VERSION 5.7 ;
  NOWIREEXTENSIONATPIN ON ;
  DIVIDERCHAR "/" ;
  BUSBITCHARS "[]" ;
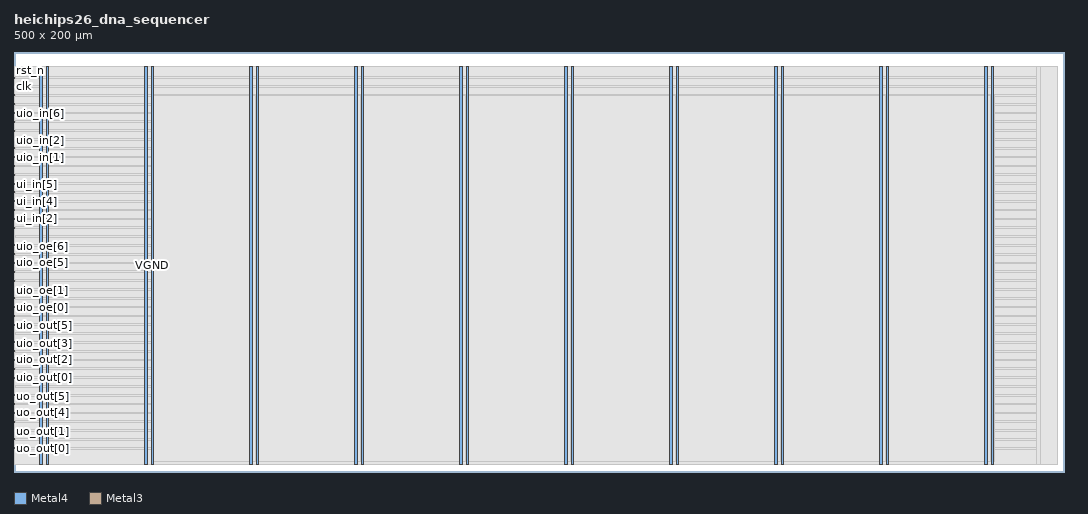
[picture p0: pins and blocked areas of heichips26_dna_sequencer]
MACRO heichips26_dna_sequencer
  CLASS BLOCK ;
  FOREIGN heichips26_dna_sequencer ;
  ORIGIN 0.000 0.000 ;
  SIZE 500.000 BY 200.000 ;
  PIN VGND
    DIRECTION INOUT ;
    USE GROUND ;
    PORT
      LAYER Metal4 ;
        RECT 15.380 3.560 16.380 193.000 ;
    END
    PORT
      LAYER Metal4 ;
        RECT 65.380 3.560 66.380 193.000 ;
    END
    PORT
      LAYER Metal4 ;
        RECT 115.380 3.560 116.380 193.000 ;
    END
    PORT
      LAYER Metal4 ;
        RECT 165.380 3.560 166.380 193.000 ;
    END
    PORT
      LAYER Metal4 ;
        RECT 215.380 3.560 216.380 193.000 ;
    END
    PORT
      LAYER Metal4 ;
        RECT 265.380 3.560 266.380 193.000 ;
    END
    PORT
      LAYER Metal4 ;
        RECT 315.380 3.560 316.380 193.000 ;
    END
    PORT
      LAYER Metal4 ;
        RECT 365.380 3.560 366.380 193.000 ;
    END
    PORT
      LAYER Metal4 ;
        RECT 415.380 3.560 416.380 193.000 ;
    END
    PORT
      LAYER Metal4 ;
        RECT 465.380 3.560 466.380 193.000 ;
    END
  END VGND
  PIN VPWR
    DIRECTION INOUT ;
    USE POWER ;
    PORT
      LAYER Metal4 ;
        RECT 12.380 3.560 13.380 193.000 ;
    END
    PORT
      LAYER Metal4 ;
        RECT 62.380 3.560 63.380 193.000 ;
    END
    PORT
      LAYER Metal4 ;
        RECT 112.380 3.560 113.380 193.000 ;
    END
    PORT
      LAYER Metal4 ;
        RECT 162.380 3.560 163.380 193.000 ;
    END
    PORT
      LAYER Metal4 ;
        RECT 212.380 3.560 213.380 193.000 ;
    END
    PORT
      LAYER Metal4 ;
        RECT 262.380 3.560 263.380 193.000 ;
    END
    PORT
      LAYER Metal4 ;
        RECT 312.380 3.560 313.380 193.000 ;
    END
    PORT
      LAYER Metal4 ;
        RECT 362.380 3.560 363.380 193.000 ;
    END
    PORT
      LAYER Metal4 ;
        RECT 412.380 3.560 413.380 193.000 ;
    END
    PORT
      LAYER Metal4 ;
        RECT 462.380 3.560 463.380 193.000 ;
    END
  END VPWR
  PIN clk
    DIRECTION INPUT ;
    USE SIGNAL ;
    ANTENNAGATEAREA 0.725400 ;
    PORT
      LAYER Metal3 ;
        RECT 0.000 183.340 0.400 183.740 ;
    END
  END clk
  PIN ena
    DIRECTION INPUT ;
    USE SIGNAL ;
    PORT
      LAYER Metal3 ;
        RECT 0.000 179.140 0.400 179.540 ;
    END
  END ena
  PIN rst_n
    DIRECTION INPUT ;
    USE SIGNAL ;
    ANTENNAGATEAREA 0.180700 ;
    PORT
      LAYER Metal3 ;
        RECT 0.000 187.540 0.400 187.940 ;
    END
  END rst_n
  PIN ui_in[0]
    DIRECTION INPUT ;
    USE SIGNAL ;
    ANTENNAGATEAREA 0.180700 ;
    PORT
      LAYER Metal3 ;
        RECT 0.000 111.940 0.400 112.340 ;
    END
  END ui_in[0]
  PIN ui_in[1]
    DIRECTION INPUT ;
    USE SIGNAL ;
    ANTENNAGATEAREA 0.180700 ;
    PORT
      LAYER Metal3 ;
        RECT 0.000 116.140 0.400 116.540 ;
    END
  END ui_in[1]
  PIN ui_in[2]
    DIRECTION INPUT ;
    USE SIGNAL ;
    ANTENNAGATEAREA 0.180700 ;
    PORT
      LAYER Metal3 ;
        RECT 0.000 120.340 0.400 120.740 ;
    END
  END ui_in[2]
  PIN ui_in[3]
    DIRECTION INPUT ;
    USE SIGNAL ;
    ANTENNAGATEAREA 0.180700 ;
    PORT
      LAYER Metal3 ;
        RECT 0.000 124.540 0.400 124.940 ;
    END
  END ui_in[3]
  PIN ui_in[4]
    DIRECTION INPUT ;
    USE SIGNAL ;
    PORT
      LAYER Metal3 ;
        RECT 0.000 128.740 0.400 129.140 ;
    END
  END ui_in[4]
  PIN ui_in[5]
    DIRECTION INPUT ;
    USE SIGNAL ;
    PORT
      LAYER Metal3 ;
        RECT 0.000 132.940 0.400 133.340 ;
    END
  END ui_in[5]
  PIN ui_in[6]
    DIRECTION INPUT ;
    USE SIGNAL ;
    PORT
      LAYER Metal3 ;
        RECT 0.000 137.140 0.400 137.540 ;
    END
  END ui_in[6]
  PIN ui_in[7]
    DIRECTION INPUT ;
    USE SIGNAL ;
    PORT
      LAYER Metal3 ;
        RECT 0.000 141.340 0.400 141.740 ;
    END
  END ui_in[7]
  PIN uio_in[0]
    DIRECTION INPUT ;
    USE SIGNAL ;
    ANTENNAGATEAREA 0.180700 ;
    PORT
      LAYER Metal3 ;
        RECT 0.000 145.540 0.400 145.940 ;
    END
  END uio_in[0]
  PIN uio_in[1]
    DIRECTION INPUT ;
    USE SIGNAL ;
    ANTENNAGATEAREA 0.180700 ;
    PORT
      LAYER Metal3 ;
        RECT 0.000 149.740 0.400 150.140 ;
    END
  END uio_in[1]
  PIN uio_in[2]
    DIRECTION INPUT ;
    USE SIGNAL ;
    ANTENNAGATEAREA 0.180700 ;
    PORT
      LAYER Metal3 ;
        RECT 0.000 153.940 0.400 154.340 ;
    END
  END uio_in[2]
  PIN uio_in[3]
    DIRECTION INPUT ;
    USE SIGNAL ;
    ANTENNAGATEAREA 0.180700 ;
    PORT
      LAYER Metal3 ;
        RECT 0.000 158.140 0.400 158.540 ;
    END
  END uio_in[3]
  PIN uio_in[4]
    DIRECTION INPUT ;
    USE SIGNAL ;
    ANTENNAGATEAREA 0.180700 ;
    PORT
      LAYER Metal3 ;
        RECT 0.000 162.340 0.400 162.740 ;
    END
  END uio_in[4]
  PIN uio_in[5]
    DIRECTION INPUT ;
    USE SIGNAL ;
    ANTENNAGATEAREA 0.180700 ;
    PORT
      LAYER Metal3 ;
        RECT 0.000 166.540 0.400 166.940 ;
    END
  END uio_in[5]
  PIN uio_in[6]
    DIRECTION INPUT ;
    USE SIGNAL ;
    ANTENNAGATEAREA 0.180700 ;
    PORT
      LAYER Metal3 ;
        RECT 0.000 170.740 0.400 171.140 ;
    END
  END uio_in[6]
  PIN uio_in[7]
    DIRECTION INPUT ;
    USE SIGNAL ;
    ANTENNAGATEAREA 0.180700 ;
    PORT
      LAYER Metal3 ;
        RECT 0.000 174.940 0.400 175.340 ;
    END
  END uio_in[7]
  PIN uio_oe[0]
    DIRECTION OUTPUT ;
    USE SIGNAL ;
    ANTENNADIFFAREA 0.299200 ;
    PORT
      LAYER Metal3 ;
        RECT 0.000 78.340 0.400 78.740 ;
    END
  END uio_oe[0]
  PIN uio_oe[1]
    DIRECTION OUTPUT ;
    USE SIGNAL ;
    ANTENNADIFFAREA 0.299200 ;
    PORT
      LAYER Metal3 ;
        RECT 0.000 82.540 0.400 82.940 ;
    END
  END uio_oe[1]
  PIN uio_oe[2]
    DIRECTION OUTPUT ;
    USE SIGNAL ;
    ANTENNADIFFAREA 0.299200 ;
    PORT
      LAYER Metal3 ;
        RECT 0.000 86.740 0.400 87.140 ;
    END
  END uio_oe[2]
  PIN uio_oe[3]
    DIRECTION OUTPUT ;
    USE SIGNAL ;
    ANTENNADIFFAREA 0.299200 ;
    PORT
      LAYER Metal3 ;
        RECT 0.000 90.940 0.400 91.340 ;
    END
  END uio_oe[3]
  PIN uio_oe[4]
    DIRECTION OUTPUT ;
    USE SIGNAL ;
    ANTENNADIFFAREA 0.299200 ;
    PORT
      LAYER Metal3 ;
        RECT 0.000 95.140 0.400 95.540 ;
    END
  END uio_oe[4]
  PIN uio_oe[5]
    DIRECTION OUTPUT ;
    USE SIGNAL ;
    ANTENNADIFFAREA 0.299200 ;
    PORT
      LAYER Metal3 ;
        RECT 0.000 99.340 0.400 99.740 ;
    END
  END uio_oe[5]
  PIN uio_oe[6]
    DIRECTION OUTPUT ;
    USE SIGNAL ;
    ANTENNADIFFAREA 0.299200 ;
    PORT
      LAYER Metal3 ;
        RECT 0.000 103.540 0.400 103.940 ;
    END
  END uio_oe[6]
  PIN uio_oe[7]
    DIRECTION OUTPUT ;
    USE SIGNAL ;
    ANTENNADIFFAREA 0.299200 ;
    PORT
      LAYER Metal3 ;
        RECT 0.000 107.740 0.400 108.140 ;
    END
  END uio_oe[7]
  PIN uio_out[0]
    DIRECTION OUTPUT ;
    USE SIGNAL ;
    ANTENNADIFFAREA 0.299200 ;
    PORT
      LAYER Metal3 ;
        RECT 0.000 44.740 0.400 45.140 ;
    END
  END uio_out[0]
  PIN uio_out[1]
    DIRECTION OUTPUT ;
    USE SIGNAL ;
    ANTENNADIFFAREA 0.299200 ;
    PORT
      LAYER Metal3 ;
        RECT 0.000 48.940 0.400 49.340 ;
    END
  END uio_out[1]
  PIN uio_out[2]
    DIRECTION OUTPUT ;
    USE SIGNAL ;
    ANTENNADIFFAREA 0.299200 ;
    PORT
      LAYER Metal3 ;
        RECT 0.000 53.140 0.400 53.540 ;
    END
  END uio_out[2]
  PIN uio_out[3]
    DIRECTION OUTPUT ;
    USE SIGNAL ;
    ANTENNADIFFAREA 0.299200 ;
    PORT
      LAYER Metal3 ;
        RECT 0.000 57.340 0.400 57.740 ;
    END
  END uio_out[3]
  PIN uio_out[4]
    DIRECTION OUTPUT ;
    USE SIGNAL ;
    ANTENNADIFFAREA 0.299200 ;
    PORT
      LAYER Metal3 ;
        RECT 0.000 61.540 0.400 61.940 ;
    END
  END uio_out[4]
  PIN uio_out[5]
    DIRECTION OUTPUT ;
    USE SIGNAL ;
    ANTENNADIFFAREA 0.299200 ;
    PORT
      LAYER Metal3 ;
        RECT 0.000 65.740 0.400 66.140 ;
    END
  END uio_out[5]
  PIN uio_out[6]
    DIRECTION OUTPUT ;
    USE SIGNAL ;
    ANTENNADIFFAREA 0.299200 ;
    PORT
      LAYER Metal3 ;
        RECT 0.000 69.940 0.400 70.340 ;
    END
  END uio_out[6]
  PIN uio_out[7]
    DIRECTION OUTPUT ;
    USE SIGNAL ;
    ANTENNADIFFAREA 0.299200 ;
    PORT
      LAYER Metal3 ;
        RECT 0.000 74.140 0.400 74.540 ;
    END
  END uio_out[7]
  PIN uo_out[0]
    DIRECTION OUTPUT ;
    USE SIGNAL ;
    ANTENNADIFFAREA 0.708600 ;
    PORT
      LAYER Metal3 ;
        RECT 0.000 11.140 0.400 11.540 ;
    END
  END uo_out[0]
  PIN uo_out[1]
    DIRECTION OUTPUT ;
    USE SIGNAL ;
    ANTENNADIFFAREA 0.708600 ;
    PORT
      LAYER Metal3 ;
        RECT 0.000 15.340 0.400 15.740 ;
    END
  END uo_out[1]
  PIN uo_out[2]
    DIRECTION OUTPUT ;
    USE SIGNAL ;
    ANTENNADIFFAREA 0.708600 ;
    PORT
      LAYER Metal3 ;
        RECT 0.000 19.540 0.400 19.940 ;
    END
  END uo_out[2]
  PIN uo_out[3]
    DIRECTION OUTPUT ;
    USE SIGNAL ;
    ANTENNADIFFAREA 0.708600 ;
    PORT
      LAYER Metal3 ;
        RECT 0.000 23.740 0.400 24.140 ;
    END
  END uo_out[3]
  PIN uo_out[4]
    DIRECTION OUTPUT ;
    USE SIGNAL ;
    ANTENNADIFFAREA 0.708600 ;
    PORT
      LAYER Metal3 ;
        RECT 0.000 27.940 0.400 28.340 ;
    END
  END uo_out[4]
  PIN uo_out[5]
    DIRECTION OUTPUT ;
    USE SIGNAL ;
    ANTENNADIFFAREA 0.708600 ;
    PORT
      LAYER Metal3 ;
        RECT 0.000 32.140 0.400 32.540 ;
    END
  END uo_out[5]
  PIN uo_out[6]
    DIRECTION OUTPUT ;
    USE SIGNAL ;
    ANTENNADIFFAREA 0.299200 ;
    PORT
      LAYER Metal3 ;
        RECT 0.000 36.340 0.400 36.740 ;
    END
  END uo_out[6]
  PIN uo_out[7]
    DIRECTION OUTPUT ;
    USE SIGNAL ;
    ANTENNADIFFAREA 0.299200 ;
    PORT
      LAYER Metal3 ;
        RECT 0.000 40.540 0.400 40.940 ;
    END
  END uo_out[7]
  OBS
      LAYER GatPoly ;
        RECT 2.880 3.630 496.800 192.930 ;
      LAYER Metal1 ;
        RECT 2.880 3.560 496.800 193.000 ;
      LAYER Metal2 ;
        RECT 0.375 3.635 488.740 192.925 ;
      LAYER Metal3 ;
        RECT 0.335 188.150 486.865 192.880 ;
        RECT 0.610 187.330 486.865 188.150 ;
        RECT 0.335 183.950 486.865 187.330 ;
        RECT 0.610 183.130 486.865 183.950 ;
        RECT 0.335 179.750 486.865 183.130 ;
        RECT 0.610 178.930 486.865 179.750 ;
        RECT 0.335 175.550 486.865 178.930 ;
        RECT 0.610 174.730 486.865 175.550 ;
        RECT 0.335 171.350 486.865 174.730 ;
        RECT 0.610 170.530 486.865 171.350 ;
        RECT 0.335 167.150 486.865 170.530 ;
        RECT 0.610 166.330 486.865 167.150 ;
        RECT 0.335 162.950 486.865 166.330 ;
        RECT 0.610 162.130 486.865 162.950 ;
        RECT 0.335 158.750 486.865 162.130 ;
        RECT 0.610 157.930 486.865 158.750 ;
        RECT 0.335 154.550 486.865 157.930 ;
        RECT 0.610 153.730 486.865 154.550 ;
        RECT 0.335 150.350 486.865 153.730 ;
        RECT 0.610 149.530 486.865 150.350 ;
        RECT 0.335 146.150 486.865 149.530 ;
        RECT 0.610 145.330 486.865 146.150 ;
        RECT 0.335 141.950 486.865 145.330 ;
        RECT 0.610 141.130 486.865 141.950 ;
        RECT 0.335 137.750 486.865 141.130 ;
        RECT 0.610 136.930 486.865 137.750 ;
        RECT 0.335 133.550 486.865 136.930 ;
        RECT 0.610 132.730 486.865 133.550 ;
        RECT 0.335 129.350 486.865 132.730 ;
        RECT 0.610 128.530 486.865 129.350 ;
        RECT 0.335 125.150 486.865 128.530 ;
        RECT 0.610 124.330 486.865 125.150 ;
        RECT 0.335 120.950 486.865 124.330 ;
        RECT 0.610 120.130 486.865 120.950 ;
        RECT 0.335 116.750 486.865 120.130 ;
        RECT 0.610 115.930 486.865 116.750 ;
        RECT 0.335 112.550 486.865 115.930 ;
        RECT 0.610 111.730 486.865 112.550 ;
        RECT 0.335 108.350 486.865 111.730 ;
        RECT 0.610 107.530 486.865 108.350 ;
        RECT 0.335 104.150 486.865 107.530 ;
        RECT 0.610 103.330 486.865 104.150 ;
        RECT 0.335 99.950 486.865 103.330 ;
        RECT 0.610 99.130 486.865 99.950 ;
        RECT 0.335 95.750 486.865 99.130 ;
        RECT 0.610 94.930 486.865 95.750 ;
        RECT 0.335 91.550 486.865 94.930 ;
        RECT 0.610 90.730 486.865 91.550 ;
        RECT 0.335 87.350 486.865 90.730 ;
        RECT 0.610 86.530 486.865 87.350 ;
        RECT 0.335 83.150 486.865 86.530 ;
        RECT 0.610 82.330 486.865 83.150 ;
        RECT 0.335 78.950 486.865 82.330 ;
        RECT 0.610 78.130 486.865 78.950 ;
        RECT 0.335 74.750 486.865 78.130 ;
        RECT 0.610 73.930 486.865 74.750 ;
        RECT 0.335 70.550 486.865 73.930 ;
        RECT 0.610 69.730 486.865 70.550 ;
        RECT 0.335 66.350 486.865 69.730 ;
        RECT 0.610 65.530 486.865 66.350 ;
        RECT 0.335 62.150 486.865 65.530 ;
        RECT 0.610 61.330 486.865 62.150 ;
        RECT 0.335 57.950 486.865 61.330 ;
        RECT 0.610 57.130 486.865 57.950 ;
        RECT 0.335 53.750 486.865 57.130 ;
        RECT 0.610 52.930 486.865 53.750 ;
        RECT 0.335 49.550 486.865 52.930 ;
        RECT 0.610 48.730 486.865 49.550 ;
        RECT 0.335 45.350 486.865 48.730 ;
        RECT 0.610 44.530 486.865 45.350 ;
        RECT 0.335 41.150 486.865 44.530 ;
        RECT 0.610 40.330 486.865 41.150 ;
        RECT 0.335 36.950 486.865 40.330 ;
        RECT 0.610 36.130 486.865 36.950 ;
        RECT 0.335 32.750 486.865 36.130 ;
        RECT 0.610 31.930 486.865 32.750 ;
        RECT 0.335 28.550 486.865 31.930 ;
        RECT 0.610 27.730 486.865 28.550 ;
        RECT 0.335 24.350 486.865 27.730 ;
        RECT 0.610 23.530 486.865 24.350 ;
        RECT 0.335 20.150 486.865 23.530 ;
        RECT 0.610 19.330 486.865 20.150 ;
        RECT 0.335 15.950 486.865 19.330 ;
        RECT 0.610 15.130 486.865 15.950 ;
        RECT 0.335 11.750 486.865 15.130 ;
        RECT 0.610 10.930 486.865 11.750 ;
        RECT 0.335 3.680 486.865 10.930 ;
      LAYER Metal4 ;
        RECT 66.620 4.895 112.170 179.065 ;
        RECT 113.590 4.895 115.170 179.065 ;
        RECT 116.590 4.895 162.170 179.065 ;
        RECT 163.590 4.895 165.170 179.065 ;
        RECT 166.590 4.895 212.170 179.065 ;
        RECT 213.590 4.895 215.170 179.065 ;
        RECT 216.590 4.895 262.170 179.065 ;
        RECT 263.590 4.895 265.170 179.065 ;
        RECT 266.590 4.895 312.170 179.065 ;
        RECT 313.590 4.895 315.170 179.065 ;
        RECT 316.590 4.895 362.170 179.065 ;
        RECT 363.590 4.895 365.170 179.065 ;
        RECT 366.590 4.895 412.170 179.065 ;
        RECT 413.590 4.895 415.170 179.065 ;
        RECT 416.590 4.895 462.170 179.065 ;
        RECT 463.590 4.895 465.170 179.065 ;
        RECT 466.590 4.895 467.140 179.065 ;
  END
END heichips26_dna_sequencer
END LIBRARY

